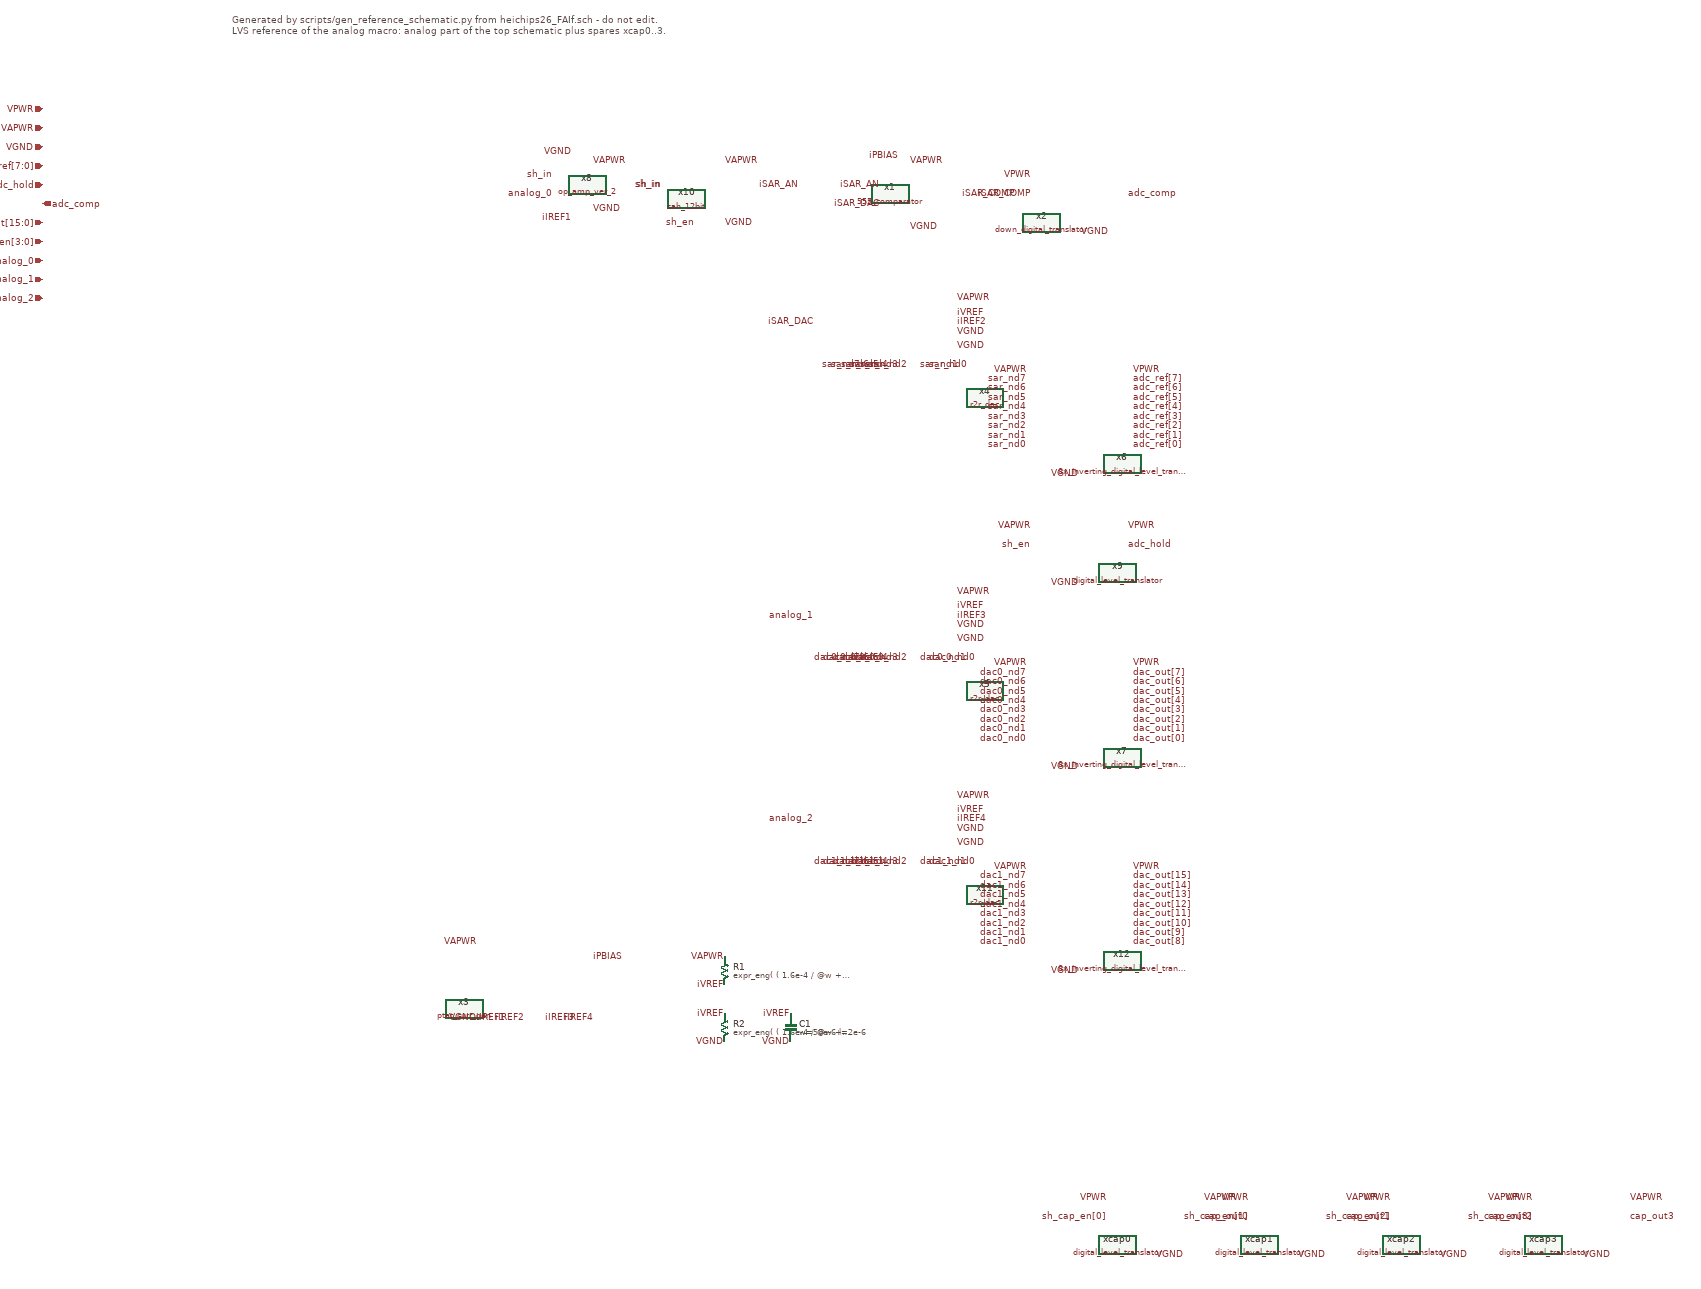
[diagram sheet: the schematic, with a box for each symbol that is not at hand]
v {xschem version=3.4.8RC file_version=1.3}
G {}
K {}
V {}
S {}
E {}
T {Generated by scripts/gen_reference_schematic.py from heichips26_FAIf.sch - do not edit.
LVS reference of the analog macro: analog part of the top schematic plus spares xcap0..3.} 100 -2400 0 0 0.6 0.6 {}
C {555_comparator.sym} 1490 -2020 0 0 {name=x1}
C {lab_pin.sym} 1530 -2090 0 1 {name=l1 sig_type=std_logic lab=VAPWR}
C {lab_pin.sym} 1510 -2100 0 0 {name=l2 sig_type=std_logic lab=iPBIAS}
C {lab_pin.sym} 1640 -2020 0 1 {name=l3 sig_type=std_logic lab=iSAR_COMP}
C {lab_pin.sym} 1470 -2040 0 0 {name=l4 sig_type=std_logic lab=iSAR_AN}
C {lab_pin.sym} 1470 -2000 0 0 {name=l5 sig_type=std_logic lab=iSAR_DAC}
C {lab_pin.sym} 1530 -1950 0 1 {name=l6 sig_type=std_logic lab=VGND}
C {down_digital_translator.sym} 1810 -1960 0 0 {name=x2}
C {lab_pin.sym} 1790 -2060 0 0 {name=l7 sig_type=std_logic lab=VPWR}
C {lab_pin.sym} 1790 -2020 0 0 {name=l8 sig_type=std_logic lab=iSAR_COMP}
C {lab_pin.sym} 1990 -2020 0 1 {name=l9 sig_type=std_logic lab=adc_comp}
C {lab_pin.sym} 1890 -1940 0 1 {name=l10 sig_type=std_logic lab=VGND}
C {ptat_curr_gen.sym} 590 -300 0 0 {name=x3}
C {lab_pin.sym} 620 -440 0 0 {name=l11 sig_type=std_logic lab=VAPWR}
C {lab_pin.sym} 680 -280 0 0 {name=l12 sig_type=std_logic lab=iIREF1}
C {lab_pin.sym} 720 -280 0 0 {name=l13 sig_type=std_logic lab=iIREF2}
C {lab_pin.sym} 760 -280 0 1 {name=l14 sig_type=std_logic lab=iIREF3}
C {lab_pin.sym} 860 -410 0 1 {name=l15 sig_type=std_logic lab=iPBIAS}
C {lab_pin.sym} 620 -280 0 0 {name=l16 sig_type=std_logic lab=VGND}
C {lab_pin.sym} 800 -280 0 1 {name=l17 sig_type=std_logic lab=iIREF4}
C {r2r_dac.sym} 1690 -1590 0 1 {name=x4}
C {lab_pin.sym} 1630 -1800 0 1 {name=l18 sig_type=std_logic lab=VAPWR}
C {lab_pin.sym} 1330 -1750 0 0 {name=l19 sig_type=std_logic lab=iSAR_DAC}
C {lab_pin.sym} 1630 -1770 0 1 {name=l20 sig_type=std_logic lab=iVREF}
C {lab_pin.sym} 1630 -1750 0 1 {name=l21 sig_type=std_logic lab=iIREF2}
C {lab_pin.sym} 1430 -1660 0 0 {name=l22 sig_type=std_logic lab=sar_nd7}
C {lab_pin.sym} 1570 -1660 0 1 {name=l23 sig_type=std_logic lab=sar_nd0}
C {lab_pin.sym} 1530 -1660 0 0 {name=l24 sig_type=std_logic lab=sar_nd2}
C {lab_pin.sym} 1490 -1660 0 0 {name=l25 sig_type=std_logic lab=sar_nd4}
C {lab_pin.sym} 1470 -1660 0 0 {name=l26 sig_type=std_logic lab=sar_nd5}
C {lab_pin.sym} 1450 -1660 0 0 {name=l27 sig_type=std_logic lab=sar_nd6}
C {lab_pin.sym} 1510 -1660 0 0 {name=l28 sig_type=std_logic lab=sar_nd3}
C {lab_pin.sym} 1550 -1660 0 1 {name=l29 sig_type=std_logic lab=sar_nd1}
C {lab_pin.sym} 1630 -1700 0 1 {name=l30 sig_type=std_logic lab=VGND}
C {lab_pin.sym} 1630 -1730 0 1 {name=l31 sig_type=std_logic lab=VGND}
C {r2r_dac.sym} 1690 -970 0 1 {name=x5}
C {lab_pin.sym} 1630 -1180 0 1 {name=l32 sig_type=std_logic lab=VAPWR}
C {lab_pin.sym} 1330 -1130 0 0 {name=l33 sig_type=std_logic lab=analog_1}
C {lab_pin.sym} 1630 -1150 0 1 {name=l34 sig_type=std_logic lab=iVREF}
C {lab_pin.sym} 1630 -1130 0 1 {name=l35 sig_type=std_logic lab=iIREF3}
C {lab_pin.sym} 1430 -1040 0 0 {name=l36 sig_type=std_logic lab=dac0_nd7}
C {lab_pin.sym} 1570 -1040 0 1 {name=l37 sig_type=std_logic lab=dac0_nd0}
C {lab_pin.sym} 1530 -1040 0 0 {name=l38 sig_type=std_logic lab=dac0_nd2}
C {lab_pin.sym} 1490 -1040 0 0 {name=l39 sig_type=std_logic lab=dac0_nd4}
C {lab_pin.sym} 1470 -1040 0 0 {name=l40 sig_type=std_logic lab=dac0_nd5}
C {lab_pin.sym} 1450 -1040 0 0 {name=l41 sig_type=std_logic lab=dac0_nd6}
C {lab_pin.sym} 1510 -1040 0 0 {name=l42 sig_type=std_logic lab=dac0_nd3}
C {lab_pin.sym} 1550 -1040 0 1 {name=l43 sig_type=std_logic lab=dac0_nd1}
C {lab_pin.sym} 1630 -1080 0 1 {name=l44 sig_type=std_logic lab=VGND}
C {lab_pin.sym} 1630 -1110 0 1 {name=l45 sig_type=std_logic lab=VGND}
C {8x_inverting_digital_level_translator.sym} 1980 -1450 0 1 {name=x6}
C {lab_pin.sym} 2000 -1650 0 1 {name=l46 sig_type=std_logic lab=VPWR}
C {lab_pin.sym} 1780 -1650 0 0 {name=l47 sig_type=std_logic lab=VAPWR}
C {lab_pin.sym} 1780 -1630 0 0 {name=l48 sig_type=std_logic lab=sar_nd7}
C {lab_pin.sym} 2000 -1630 0 1 {name=l49 sig_type=std_logic lab=adc_ref[7]}
C {lab_pin.sym} 1780 -1610 0 0 {name=l50 sig_type=std_logic lab=sar_nd6}
C {lab_pin.sym} 2000 -1610 0 1 {name=l51 sig_type=std_logic lab=adc_ref[6]}
C {lab_pin.sym} 1780 -1590 0 0 {name=l52 sig_type=std_logic lab=sar_nd5}
C {lab_pin.sym} 2000 -1590 0 1 {name=l53 sig_type=std_logic lab=adc_ref[5]}
C {lab_pin.sym} 1780 -1570 0 0 {name=l54 sig_type=std_logic lab=sar_nd4}
C {lab_pin.sym} 2000 -1570 0 1 {name=l55 sig_type=std_logic lab=adc_ref[4]}
C {lab_pin.sym} 2000 -1550 0 1 {name=l56 sig_type=std_logic lab=adc_ref[3]}
C {lab_pin.sym} 1780 -1550 0 0 {name=l57 sig_type=std_logic lab=sar_nd3}
C {lab_pin.sym} 2000 -1530 0 1 {name=l58 sig_type=std_logic lab=adc_ref[2]}
C {lab_pin.sym} 1780 -1530 0 0 {name=l59 sig_type=std_logic lab=sar_nd2}
C {lab_pin.sym} 1780 -1510 0 0 {name=l60 sig_type=std_logic lab=sar_nd1}
C {lab_pin.sym} 2000 -1510 0 1 {name=l61 sig_type=std_logic lab=adc_ref[1]}
C {lab_pin.sym} 2000 -1490 0 1 {name=l62 sig_type=std_logic lab=adc_ref[0]}
C {lab_pin.sym} 1780 -1490 0 0 {name=l63 sig_type=std_logic lab=sar_nd0}
C {lab_pin.sym} 1890 -1430 0 0 {name=l64 sig_type=std_logic lab=VGND}
C {8x_inverting_digital_level_translator.sym} 1980 -830 0 1 {name=x7}
C {lab_pin.sym} 2000 -1030 0 1 {name=l65 sig_type=std_logic lab=VPWR}
C {lab_pin.sym} 1780 -1030 0 0 {name=l66 sig_type=std_logic lab=VAPWR}
C {lab_pin.sym} 1780 -1010 0 0 {name=l67 sig_type=std_logic lab=dac0_nd7}
C {lab_pin.sym} 2000 -1010 0 1 {name=l68 sig_type=std_logic lab=dac_out[7]}
C {lab_pin.sym} 1780 -990 0 0 {name=l69 sig_type=std_logic lab=dac0_nd6}
C {lab_pin.sym} 2000 -990 0 1 {name=l70 sig_type=std_logic lab=dac_out[6]}
C {lab_pin.sym} 1780 -970 0 0 {name=l71 sig_type=std_logic lab=dac0_nd5}
C {lab_pin.sym} 2000 -970 0 1 {name=l72 sig_type=std_logic lab=dac_out[5]}
C {lab_pin.sym} 1780 -950 0 0 {name=l73 sig_type=std_logic lab=dac0_nd4}
C {lab_pin.sym} 2000 -950 0 1 {name=l74 sig_type=std_logic lab=dac_out[4]}
C {lab_pin.sym} 2000 -930 0 1 {name=l75 sig_type=std_logic lab=dac_out[3]}
C {lab_pin.sym} 1780 -930 0 0 {name=l76 sig_type=std_logic lab=dac0_nd3}
C {lab_pin.sym} 2000 -910 0 1 {name=l77 sig_type=std_logic lab=dac_out[2]}
C {lab_pin.sym} 1780 -910 0 0 {name=l78 sig_type=std_logic lab=dac0_nd2}
C {lab_pin.sym} 1780 -890 0 0 {name=l79 sig_type=std_logic lab=dac0_nd1}
C {lab_pin.sym} 2000 -890 0 1 {name=l80 sig_type=std_logic lab=dac_out[1]}
C {lab_pin.sym} 2000 -870 0 1 {name=l81 sig_type=std_logic lab=dac_out[0]}
C {lab_pin.sym} 1780 -870 0 0 {name=l82 sig_type=std_logic lab=dac0_nd0}
C {lab_pin.sym} 1890 -810 0 0 {name=l83 sig_type=std_logic lab=VGND}
C {op_amp_ver_2.sym} 850 -2040 0 0 {name=x8}
C {lab_pin.sym} 860 -2090 0 1 {name=l84 sig_type=std_logic lab=VAPWR}
C {lab_pin.sym} 820 -1970 0 0 {name=l85 sig_type=std_logic lab=iIREF1}
C {lab_pin.sym} 780 -2060 0 0 {name=l86 sig_type=std_logic lab=sh_in}
C {lab_pin.sym} 950 -2040 0 1 {name=l87 sig_type=std_logic lab=sh_in}
C {lab_pin.sym} 780 -2020 0 0 {name=l88 sig_type=std_logic lab=analog_0}
C {lab_pin.sym} 860 -1990 0 1 {name=l89 sig_type=std_logic lab=VGND}
C {lab_pin.sym} 820 -2110 0 0 {name=l90 sig_type=std_logic lab=VGND}
C {digital_level_translator.sym} 1970 -1220 0 1 {name=x9}
C {lab_pin.sym} 1790 -1320 0 0 {name=l91 sig_type=std_logic lab=VAPWR}
C {lab_pin.sym} 1990 -1320 0 1 {name=l92 sig_type=std_logic lab=VPWR}
C {lab_pin.sym} 1990 -1280 0 1 {name=l93 sig_type=std_logic lab=adc_hold}
C {lab_pin.sym} 1790 -1280 0 0 {name=l94 sig_type=std_logic lab=sh_en}
C {lab_pin.sym} 1890 -1200 0 0 {name=l95 sig_type=std_logic lab=VGND}
C {sah_12bit.sym} 1060 -2010 0 0 {name=x10}
C {lab_pin.sym} 1140 -2090 0 1 {name=l96 sig_type=std_logic lab=VAPWR}
C {lab_pin.sym} 1010 -2040 0 0 {name=l97 sig_type=std_logic lab=sh_in}
C {lab_pin.sym} 1210 -2040 0 1 {name=l98 sig_type=std_logic lab=iSAR_AN}
C {lab_pin.sym} 1080 -1960 0 0 {name=l99 sig_type=std_logic lab=sh_en}
C {lab_pin.sym} 1140 -1960 0 1 {name=l100 sig_type=std_logic lab=VGND}
C {r2r_dac.sym} 1690 -540 0 1 {name=x11}
C {lab_pin.sym} 1630 -750 0 1 {name=l101 sig_type=std_logic lab=VAPWR}
C {lab_pin.sym} 1330 -700 0 0 {name=l102 sig_type=std_logic lab=analog_2}
C {lab_pin.sym} 1630 -720 0 1 {name=l103 sig_type=std_logic lab=iVREF}
C {lab_pin.sym} 1630 -700 0 1 {name=l104 sig_type=std_logic lab=iIREF4}
C {lab_pin.sym} 1430 -610 0 0 {name=l105 sig_type=std_logic lab=dac1_nd7}
C {lab_pin.sym} 1570 -610 0 1 {name=l106 sig_type=std_logic lab=dac1_nd0}
C {lab_pin.sym} 1530 -610 0 0 {name=l107 sig_type=std_logic lab=dac1_nd2}
C {lab_pin.sym} 1490 -610 0 0 {name=l108 sig_type=std_logic lab=dac1_nd4}
C {lab_pin.sym} 1470 -610 0 0 {name=l109 sig_type=std_logic lab=dac1_nd5}
C {lab_pin.sym} 1450 -610 0 0 {name=l110 sig_type=std_logic lab=dac1_nd6}
C {lab_pin.sym} 1510 -610 0 0 {name=l111 sig_type=std_logic lab=dac1_nd3}
C {lab_pin.sym} 1550 -610 0 1 {name=l112 sig_type=std_logic lab=dac1_nd1}
C {lab_pin.sym} 1630 -650 0 1 {name=l113 sig_type=std_logic lab=VGND}
C {lab_pin.sym} 1630 -680 0 1 {name=l114 sig_type=std_logic lab=VGND}
C {8x_inverting_digital_level_translator.sym} 1980 -400 0 1 {name=x12}
C {lab_pin.sym} 2000 -600 0 1 {name=l115 sig_type=std_logic lab=VPWR}
C {lab_pin.sym} 1780 -600 0 0 {name=l116 sig_type=std_logic lab=VAPWR}
C {lab_pin.sym} 1780 -580 0 0 {name=l117 sig_type=std_logic lab=dac1_nd7}
C {lab_pin.sym} 2000 -580 0 1 {name=l118 sig_type=std_logic lab=dac_out[15]}
C {lab_pin.sym} 1780 -560 0 0 {name=l119 sig_type=std_logic lab=dac1_nd6}
C {lab_pin.sym} 2000 -560 0 1 {name=l120 sig_type=std_logic lab=dac_out[14]}
C {lab_pin.sym} 1780 -540 0 0 {name=l121 sig_type=std_logic lab=dac1_nd5}
C {lab_pin.sym} 2000 -540 0 1 {name=l122 sig_type=std_logic lab=dac_out[13]}
C {lab_pin.sym} 1780 -520 0 0 {name=l123 sig_type=std_logic lab=dac1_nd4}
C {lab_pin.sym} 2000 -520 0 1 {name=l124 sig_type=std_logic lab=dac_out[12]}
C {lab_pin.sym} 2000 -500 0 1 {name=l125 sig_type=std_logic lab=dac_out[11]}
C {lab_pin.sym} 1780 -500 0 0 {name=l126 sig_type=std_logic lab=dac1_nd3}
C {lab_pin.sym} 2000 -480 0 1 {name=l127 sig_type=std_logic lab=dac_out[10]}
C {lab_pin.sym} 1780 -480 0 0 {name=l128 sig_type=std_logic lab=dac1_nd2}
C {lab_pin.sym} 1780 -460 0 0 {name=l129 sig_type=std_logic lab=dac1_nd1}
C {lab_pin.sym} 2000 -460 0 1 {name=l130 sig_type=std_logic lab=dac_out[9]}
C {lab_pin.sym} 2000 -440 0 1 {name=l131 sig_type=std_logic lab=dac_out[8]}
C {lab_pin.sym} 1780 -440 0 0 {name=l132 sig_type=std_logic lab=dac1_nd0}
C {lab_pin.sym} 1890 -380 0 0 {name=l133 sig_type=std_logic lab=VGND}
C {sg13cmos5l_pr/rhigh.sym} 1140 -380 0 0 {name=R1
w=0.5e-6
l=50e-6
model=rhigh
body=VGND
spiceprefix=X
b=0
 m=1
  mm_ok=1
value="expr_eng(  ( 1.6e-4 / @w + 1360.0 * ( (@b + 1)* @l + ( 1.081*( @w - 0.04e-6 ) + 0.18e-6 )*@b ) / ( @w - 0.04e-6 ) ) / @m  )"
}
C {lab_pin.sym} 1140 -410 0 0 {name=l134 sig_type=std_logic lab=VAPWR}
C {lab_pin.sym} 1140 -350 0 0 {name=l135 sig_type=std_logic lab=iVREF}
C {sg13cmos5l_pr/rhigh.sym} 1140 -260 0 0 {name=R2
w=0.5e-6
l=50e-6
model=rhigh
body=VGND
spiceprefix=X
b=0
 m=1
  mm_ok=1
value="expr_eng(  ( 1.6e-4 / @w + 1360.0 * ( (@b + 1)* @l + ( 1.081*( @w - 0.04e-6 ) + 0.18e-6 )*@b ) / ( @w - 0.04e-6 ) ) / @m  )"
}
C {lab_pin.sym} 1140 -290 0 0 {name=l136 sig_type=std_logic lab=iVREF}
C {lab_pin.sym} 1140 -230 0 0 {name=l137 sig_type=std_logic lab=VGND}
C {sg13cmos5l_pr/cap_cmomi.sym} 1280 -260 0 0 {name=C1
model=cap_cmomi
w=50e-6
l=2e-6
mmin=2
mmax=3
feed=double
subblock=0
m=1
mm_ok=1
spiceprefix=X
}
C {lab_pin.sym} 1280 -290 0 0 {name=l138 sig_type=std_logic lab=iVREF}
C {lab_pin.sym} 1280 -230 0 0 {name=l139 sig_type=std_logic lab=VGND}
C {digital_level_translator.sym} 1970 200 0 0 {name=xcap0}
C {lab_pin.sym} 2150 100 0 1 {name=l140 sig_type=std_logic lab=VAPWR}
C {lab_pin.sym} 1950 100 0 0 {name=l141 sig_type=std_logic lab=VPWR}
C {lab_pin.sym} 1950 140 0 0 {name=l142 sig_type=std_logic lab=sh_cap_en[0]}
C {lab_pin.sym} 2150 140 0 1 {name=l143 sig_type=std_logic lab=cap_out0}
C {lab_pin.sym} 2050 220 0 1 {name=l144 sig_type=std_logic lab=VGND}
C {digital_level_translator.sym} 2270 200 0 0 {name=xcap1}
C {lab_pin.sym} 2450 100 0 1 {name=l145 sig_type=std_logic lab=VAPWR}
C {lab_pin.sym} 2250 100 0 0 {name=l146 sig_type=std_logic lab=VPWR}
C {lab_pin.sym} 2250 140 0 0 {name=l147 sig_type=std_logic lab=sh_cap_en[1]}
C {lab_pin.sym} 2450 140 0 1 {name=l148 sig_type=std_logic lab=cap_out1}
C {lab_pin.sym} 2350 220 0 1 {name=l149 sig_type=std_logic lab=VGND}
C {digital_level_translator.sym} 2570 200 0 0 {name=xcap2}
C {lab_pin.sym} 2750 100 0 1 {name=l150 sig_type=std_logic lab=VAPWR}
C {lab_pin.sym} 2550 100 0 0 {name=l151 sig_type=std_logic lab=VPWR}
C {lab_pin.sym} 2550 140 0 0 {name=l152 sig_type=std_logic lab=sh_cap_en[2]}
C {lab_pin.sym} 2750 140 0 1 {name=l153 sig_type=std_logic lab=cap_out2}
C {lab_pin.sym} 2650 220 0 1 {name=l154 sig_type=std_logic lab=VGND}
C {digital_level_translator.sym} 2870 200 0 0 {name=xcap3}
C {lab_pin.sym} 3050 100 0 1 {name=l155 sig_type=std_logic lab=VAPWR}
C {lab_pin.sym} 2850 100 0 0 {name=l156 sig_type=std_logic lab=VPWR}
C {lab_pin.sym} 2850 140 0 0 {name=l157 sig_type=std_logic lab=sh_cap_en[3]}
C {lab_pin.sym} 3050 140 0 1 {name=l158 sig_type=std_logic lab=cap_out3}
C {lab_pin.sym} 2950 220 0 1 {name=l159 sig_type=std_logic lab=VGND}
C {iopin.sym} -300 -2200 0 0 {name=p0 lab=VPWR}
C {iopin.sym} -300 -2160 0 0 {name=p1 lab=VAPWR}
C {iopin.sym} -300 -2120 0 0 {name=p2 lab=VGND}
C {ipin.sym} -300 -2080 0 0 {name=p3 lab=adc_ref[7:0]}
C {ipin.sym} -300 -2040 0 0 {name=p4 lab=adc_hold}
C {opin.sym} -300 -2000 0 0 {name=p5 lab=adc_comp}
C {ipin.sym} -300 -1960 0 0 {name=p6 lab=dac_out[15:0]}
C {ipin.sym} -300 -1920 0 0 {name=p7 lab=sh_cap_en[3:0]}
C {iopin.sym} -300 -1880 0 0 {name=p8 lab=analog_0}
C {iopin.sym} -300 -1840 0 0 {name=p9 lab=analog_1}
C {iopin.sym} -300 -1800 0 0 {name=p10 lab=analog_2}
